One B-rep face of a CAD part: STEP entity #116147.
In plain terms, the planar face has unit normal (0, 0, 1).
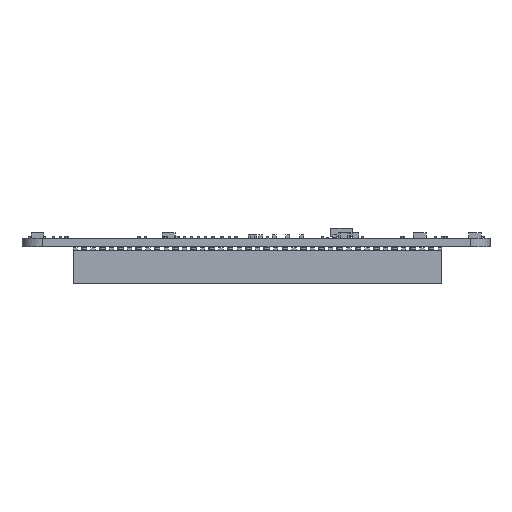
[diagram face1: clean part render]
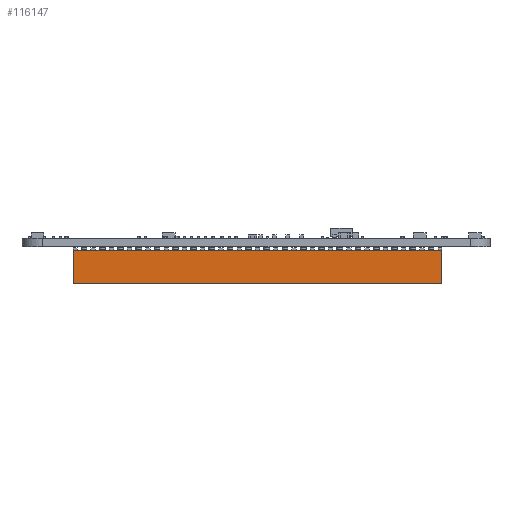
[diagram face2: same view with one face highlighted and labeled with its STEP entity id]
Its self-contained STEP definition (entity closure, numbers rounded to 3 decimals):
#76296 = PLANE('',#76297);
#76297 = AXIS2_PLACEMENT_3D('',#76298,#76299,#76300);
#76298 = CARTESIAN_POINT('',(-25.65,0.4,2.1));
#76299 = DIRECTION('',(0.,-1.,0.));
#76300 = DIRECTION('',(0.,0.,-1.));
#76321 = VERTEX_POINT('',#76322);
#76322 = CARTESIAN_POINT('',(25.65,0.4,2.6));
#76336 = PLANE('',#76337);
#76337 = AXIS2_PLACEMENT_3D('',#76338,#76339,#76340);
#76338 = CARTESIAN_POINT('',(25.65,2.52,0.));
#76339 = DIRECTION('',(1.,0.,0.));
#76340 = DIRECTION('',(0.,0.,-1.));
#76348 = EDGE_CURVE('',#76349,#76321,#76351,.T.);
#76349 = VERTEX_POINT('',#76350);
#76350 = CARTESIAN_POINT('',(-25.65,0.4,2.6));
#76351 = SURFACE_CURVE('',#76352,(#76356,#76363),.PCURVE_S1.);
#76352 = LINE('',#76353,#76354);
#76353 = CARTESIAN_POINT('',(-25.65,0.4,2.6));
#76354 = VECTOR('',#76355,1.);
#76355 = DIRECTION('',(1.,0.,0.));
#76356 = PCURVE('',#76296,#76357);
#76357 = DEFINITIONAL_REPRESENTATION('',(#76358),#76362);
#76358 = LINE('',#76359,#76360);
#76359 = CARTESIAN_POINT('',(-0.5,0.));
#76360 = VECTOR('',#76361,1.);
#76361 = DIRECTION('',(0.,1.));
#76362 = ( GEOMETRIC_REPRESENTATION_CONTEXT(2) 
PARAMETRIC_REPRESENTATION_CONTEXT() REPRESENTATION_CONTEXT('2D SPACE',''
  ) );
#76363 = PCURVE('',#76364,#76369);
#76364 = PLANE('',#76365);
#76365 = AXIS2_PLACEMENT_3D('',#76366,#76367,#76368);
#76366 = CARTESIAN_POINT('',(-25.65,0.4,2.6));
#76367 = DIRECTION('',(0.,0.,1.));
#76368 = DIRECTION('',(0.,-1.,0.));
#76369 = DEFINITIONAL_REPRESENTATION('',(#76370),#76374);
#76370 = LINE('',#76371,#76372);
#76371 = CARTESIAN_POINT('',(0.,0.));
#76372 = VECTOR('',#76373,1.);
#76373 = DIRECTION('',(0.,1.));
#76374 = ( GEOMETRIC_REPRESENTATION_CONTEXT(2) 
PARAMETRIC_REPRESENTATION_CONTEXT() REPRESENTATION_CONTEXT('2D SPACE',''
  ) );
#76392 = PLANE('',#76393);
#76393 = AXIS2_PLACEMENT_3D('',#76394,#76395,#76396);
#76394 = CARTESIAN_POINT('',(-25.65,2.52,0.)
  );
#76395 = DIRECTION('',(1.,0.,0.));
#76396 = DIRECTION('',(0.,0.,-1.));
#91990 = PLANE('',#91991);
#91991 = AXIS2_PLACEMENT_3D('',#91992,#91993,#91994);
#91992 = CARTESIAN_POINT('',(-25.65,5.,2.6));
#91993 = DIRECTION('',(0.,1.,0.));
#91994 = DIRECTION('',(0.,0.,1.));
#116147 = ADVANCED_FACE('',(#116148),#76364,.T.);
#116148 = FACE_BOUND('',#116149,.T.);
#116149 = EDGE_LOOP('',(#116150,#116173,#116196,#116217));
#116150 = ORIENTED_EDGE('',*,*,#116151,.T.);
#116151 = EDGE_CURVE('',#76321,#116152,#116154,.T.);
#116152 = VERTEX_POINT('',#116153);
#116153 = CARTESIAN_POINT('',(25.65,5.,2.6));
#116154 = SURFACE_CURVE('',#116155,(#116159,#116166),.PCURVE_S1.);
#116155 = LINE('',#116156,#116157);
#116156 = CARTESIAN_POINT('',(25.65,5.,2.6));
#116157 = VECTOR('',#116158,1.);
#116158 = DIRECTION('',(0.,1.,0.));
#116159 = PCURVE('',#76364,#116160);
#116160 = DEFINITIONAL_REPRESENTATION('',(#116161),#116165);
#116161 = LINE('',#116162,#116163);
#116162 = CARTESIAN_POINT('',(-4.6,51.3));
#116163 = VECTOR('',#116164,1.);
#116164 = DIRECTION('',(-1.,0.));
#116165 = ( GEOMETRIC_REPRESENTATION_CONTEXT(2) 
PARAMETRIC_REPRESENTATION_CONTEXT() REPRESENTATION_CONTEXT('2D SPACE',''
  ) );
#116166 = PCURVE('',#76336,#116167);
#116167 = DEFINITIONAL_REPRESENTATION('',(#116168),#116172);
#116168 = LINE('',#116169,#116170);
#116169 = CARTESIAN_POINT('',(-2.6,2.48));
#116170 = VECTOR('',#116171,1.);
#116171 = DIRECTION('',(0.,1.));
#116172 = ( GEOMETRIC_REPRESENTATION_CONTEXT(2) 
PARAMETRIC_REPRESENTATION_CONTEXT() REPRESENTATION_CONTEXT('2D SPACE',''
  ) );
#116173 = ORIENTED_EDGE('',*,*,#116174,.F.);
#116174 = EDGE_CURVE('',#116175,#116152,#116177,.T.);
#116175 = VERTEX_POINT('',#116176);
#116176 = CARTESIAN_POINT('',(-25.65,5.,2.6));
#116177 = SURFACE_CURVE('',#116178,(#116182,#116189),.PCURVE_S1.);
#116178 = LINE('',#116179,#116180);
#116179 = CARTESIAN_POINT('',(-25.65,5.,2.6));
#116180 = VECTOR('',#116181,1.);
#116181 = DIRECTION('',(1.,0.,0.));
#116182 = PCURVE('',#76364,#116183);
#116183 = DEFINITIONAL_REPRESENTATION('',(#116184),#116188);
#116184 = LINE('',#116185,#116186);
#116185 = CARTESIAN_POINT('',(-4.6,0.));
#116186 = VECTOR('',#116187,1.);
#116187 = DIRECTION('',(0.,1.));
#116188 = ( GEOMETRIC_REPRESENTATION_CONTEXT(2) 
PARAMETRIC_REPRESENTATION_CONTEXT() REPRESENTATION_CONTEXT('2D SPACE',''
  ) );
#116189 = PCURVE('',#91990,#116190);
#116190 = DEFINITIONAL_REPRESENTATION('',(#116191),#116195);
#116191 = LINE('',#116192,#116193);
#116192 = CARTESIAN_POINT('',(0.,0.));
#116193 = VECTOR('',#116194,1.);
#116194 = DIRECTION('',(0.,1.));
#116195 = ( GEOMETRIC_REPRESENTATION_CONTEXT(2) 
PARAMETRIC_REPRESENTATION_CONTEXT() REPRESENTATION_CONTEXT('2D SPACE',''
  ) );
#116196 = ORIENTED_EDGE('',*,*,#116197,.T.);
#116197 = EDGE_CURVE('',#116175,#76349,#116198,.T.);
#116198 = SURFACE_CURVE('',#116199,(#116203,#116210),.PCURVE_S1.);
#116199 = LINE('',#116200,#116201);
#116200 = CARTESIAN_POINT('',(-25.65,5.,2.6));
#116201 = VECTOR('',#116202,1.);
#116202 = DIRECTION('',(0.,-1.,0.));
#116203 = PCURVE('',#76364,#116204);
#116204 = DEFINITIONAL_REPRESENTATION('',(#116205),#116209);
#116205 = LINE('',#116206,#116207);
#116206 = CARTESIAN_POINT('',(-4.6,0.));
#116207 = VECTOR('',#116208,1.);
#116208 = DIRECTION('',(1.,0.));
#116209 = ( GEOMETRIC_REPRESENTATION_CONTEXT(2) 
PARAMETRIC_REPRESENTATION_CONTEXT() REPRESENTATION_CONTEXT('2D SPACE',''
  ) );
#116210 = PCURVE('',#76392,#116211);
#116211 = DEFINITIONAL_REPRESENTATION('',(#116212),#116216);
#116212 = LINE('',#116213,#116214);
#116213 = CARTESIAN_POINT('',(-2.6,2.48));
#116214 = VECTOR('',#116215,1.);
#116215 = DIRECTION('',(0.,-1.));
#116216 = ( GEOMETRIC_REPRESENTATION_CONTEXT(2) 
PARAMETRIC_REPRESENTATION_CONTEXT() REPRESENTATION_CONTEXT('2D SPACE',''
  ) );
#116217 = ORIENTED_EDGE('',*,*,#76348,.T.);
